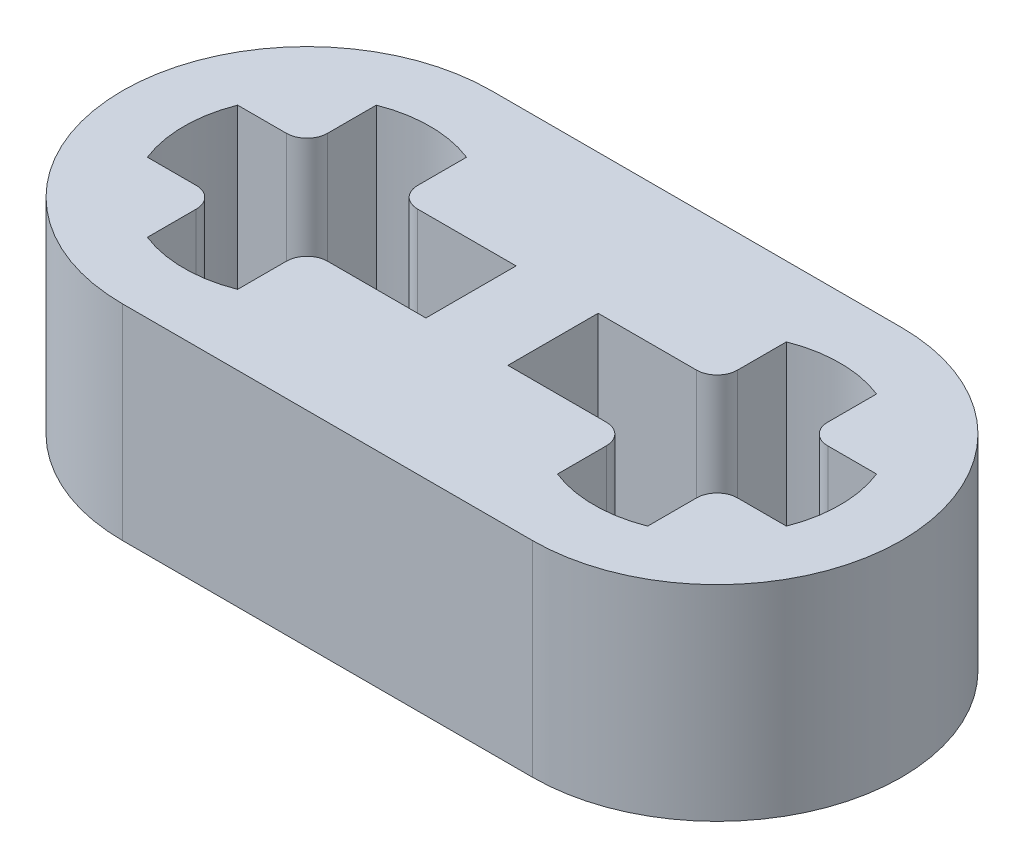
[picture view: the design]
ISO-10303-21;
HEADER;
FILE_DESCRIPTION(('STEP AP214'),'2;1');
FILE_NAME('part.step','',(''),(''),'','','');
FILE_SCHEMA(('AUTOMOTIVE_DESIGN { 1 0 10303 214 1 1 1 1 }'));
ENDSEC;
DATA;
#1=APPLICATION_CONTEXT('core data for automotive mechanical design processes');
#2=APPLICATION_PROTOCOL_DEFINITION('international standard','automotive_design',2000,#1);
#3=PRODUCT_CONTEXT('',#1,'mechanical');
#4=PRODUCT('Part','Part','',(#3));
#5=PRODUCT_RELATED_PRODUCT_CATEGORY('part','',(#4));
#6=PRODUCT_DEFINITION_FORMATION('','',#4);
#7=PRODUCT_DEFINITION_CONTEXT('part definition',#1,'design');
#8=PRODUCT_DEFINITION('design','',#6,#7);
#9=PRODUCT_DEFINITION_SHAPE('','',#8);
#10=(LENGTH_UNIT() NAMED_UNIT(*) SI_UNIT(.MILLI.,.METRE.));
#11=(NAMED_UNIT(*) PLANE_ANGLE_UNIT() SI_UNIT($,.RADIAN.));
#12=(NAMED_UNIT(*) SI_UNIT($,.STERADIAN.) SOLID_ANGLE_UNIT());
#13=UNCERTAINTY_MEASURE_WITH_UNIT(LENGTH_MEASURE(1.E-05),#10,'distance_accuracy_value','');
#14=(GEOMETRIC_REPRESENTATION_CONTEXT(3) GLOBAL_UNCERTAINTY_ASSIGNED_CONTEXT((#13)) GLOBAL_UNIT_ASSIGNED_CONTEXT((#10,
#11,#12)) REPRESENTATION_CONTEXT('',''));
#15=CARTESIAN_POINT('',(0.,0.,0.));
#16=DIRECTION('',(0.,0.,1.));
#17=DIRECTION('',(1.,0.,0.));
#18=AXIS2_PLACEMENT_3D('',#15,#16,#17);
#19=CARTESIAN_POINT('',(-4.,-2.,0.));
#20=DIRECTION('',(0.,1.,0.));
#21=DIRECTION('',(0.,0.,1.));
#22=AXIS2_PLACEMENT_3D('',#19,#20,#21);
#23=CYLINDRICAL_SURFACE('',#22,3.6);
#24=DIRECTION('',(0.,1.,0.));
#25=VECTOR('',#24,1.);
#26=CARTESIAN_POINT('',(-4.,-2.,3.6));
#27=LINE('',#26,#25);
#28=CARTESIAN_POINT('',(-4.,-2.,3.6));
#29=VERTEX_POINT('',#28);
#30=CARTESIAN_POINT('',(-4.,2.,3.6));
#31=VERTEX_POINT('',#30);
#32=EDGE_CURVE('E37',#29,#31,#27,.T.);
#33=ORIENTED_EDGE('',*,*,#32,.T.);
#34=CARTESIAN_POINT('',(-4.,2.,0.));
#35=DIRECTION('',(0.,1.,0.));
#36=DIRECTION('',(0.,0.,1.));
#37=AXIS2_PLACEMENT_3D('',#34,#35,#36);
#38=CIRCLE('',#37,3.6);
#39=CARTESIAN_POINT('',(-4.,2.,-3.6));
#40=VERTEX_POINT('',#39);
#41=EDGE_CURVE('E382',#40,#31,#38,.T.);
#42=ORIENTED_EDGE('',*,*,#41,.F.);
#43=DIRECTION('',(0.,1.,0.));
#44=VECTOR('',#43,1.);
#45=CARTESIAN_POINT('',(-4.,-2.,-3.6));
#46=LINE('',#45,#44);
#47=CARTESIAN_POINT('',(-4.,-2.,-3.6));
#48=VERTEX_POINT('',#47);
#49=EDGE_CURVE('E11',#48,#40,#46,.T.);
#50=ORIENTED_EDGE('',*,*,#49,.F.);
#51=CARTESIAN_POINT('',(-4.,-2.,0.));
#52=DIRECTION('',(0.,1.,0.));
#53=DIRECTION('',(0.,0.,1.));
#54=AXIS2_PLACEMENT_3D('',#51,#52,#53);
#55=CIRCLE('',#54,3.6);
#56=EDGE_CURVE('E513',#48,#29,#55,.T.);
#57=ORIENTED_EDGE('',*,*,#56,.T.);
#58=EDGE_LOOP('',(#33,#42,#50,#57));
#59=FACE_BOUND('',#58,.T.);
#60=ADVANCED_FACE('F34',(#59),#23,.T.);
#61=CARTESIAN_POINT('',(-4.,-2.,-3.6));
#62=DIRECTION('',(0.,0.,-1.));
#63=DIRECTION('',(-1.,0.,0.));
#64=AXIS2_PLACEMENT_3D('',#61,#62,#63);
#65=PLANE('',#64);
#66=ORIENTED_EDGE('',*,*,#49,.T.);
#67=DIRECTION('',(-1.,0.,0.));
#68=VECTOR('',#67,1.);
#69=CARTESIAN_POINT('',(-4.,2.,-3.6));
#70=LINE('',#69,#68);
#71=CARTESIAN_POINT('',(4.,2.,-3.6));
#72=VERTEX_POINT('',#71);
#73=EDGE_CURVE('E391',#72,#40,#70,.T.);
#74=ORIENTED_EDGE('',*,*,#73,.F.);
#75=DIRECTION('',(0.,1.,0.));
#76=VECTOR('',#75,1.);
#77=CARTESIAN_POINT('',(4.,-2.,-3.6));
#78=LINE('',#77,#76);
#79=CARTESIAN_POINT('',(4.,-2.,-3.6));
#80=VERTEX_POINT('',#79);
#81=EDGE_CURVE('E42',#80,#72,#78,.T.);
#82=ORIENTED_EDGE('',*,*,#81,.F.);
#83=DIRECTION('',(-1.,0.,0.));
#84=VECTOR('',#83,1.);
#85=CARTESIAN_POINT('',(-4.,-2.,-3.6));
#86=LINE('',#85,#84);
#87=EDGE_CURVE('E551',#80,#48,#86,.T.);
#88=ORIENTED_EDGE('',*,*,#87,.T.);
#89=EDGE_LOOP('',(#66,#74,#82,#88));
#90=FACE_BOUND('',#89,.T.);
#91=ADVANCED_FACE('F567',(#90),#65,.T.);
#92=CARTESIAN_POINT('',(4.,-2.,0.));
#93=DIRECTION('',(0.,1.,0.));
#94=DIRECTION('',(0.,0.,1.));
#95=AXIS2_PLACEMENT_3D('',#92,#93,#94);
#96=CYLINDRICAL_SURFACE('',#95,3.6);
#97=ORIENTED_EDGE('',*,*,#81,.T.);
#98=CARTESIAN_POINT('',(4.,2.,0.));
#99=DIRECTION('',(0.,1.,0.));
#100=DIRECTION('',(0.,0.,1.));
#101=AXIS2_PLACEMENT_3D('',#98,#99,#100);
#102=CIRCLE('',#101,3.6);
#103=CARTESIAN_POINT('',(4.,2.,3.6));
#104=VERTEX_POINT('',#103);
#105=EDGE_CURVE('E388',#104,#72,#102,.T.);
#106=ORIENTED_EDGE('',*,*,#105,.F.);
#107=DIRECTION('',(0.,1.,0.));
#108=VECTOR('',#107,1.);
#109=CARTESIAN_POINT('',(4.,-2.,3.6));
#110=LINE('',#109,#108);
#111=CARTESIAN_POINT('',(4.,-2.,3.6));
#112=VERTEX_POINT('',#111);
#113=EDGE_CURVE('E554',#112,#104,#110,.T.);
#114=ORIENTED_EDGE('',*,*,#113,.F.);
#115=CARTESIAN_POINT('',(4.,-2.,0.));
#116=DIRECTION('',(0.,1.,0.));
#117=DIRECTION('',(0.,0.,1.));
#118=AXIS2_PLACEMENT_3D('',#115,#116,#117);
#119=CIRCLE('',#118,3.6);
#120=EDGE_CURVE('E548',#112,#80,#119,.T.);
#121=ORIENTED_EDGE('',*,*,#120,.T.);
#122=EDGE_LOOP('',(#97,#106,#114,#121));
#123=FACE_BOUND('',#122,.T.);
#124=ADVANCED_FACE('F573',(#123),#96,.T.);
#125=CARTESIAN_POINT('',(-4.,-2.,3.6));
#126=DIRECTION('',(0.,0.,1.));
#127=DIRECTION('',(1.,0.,0.));
#128=AXIS2_PLACEMENT_3D('',#125,#126,#127);
#129=PLANE('',#128);
#130=ORIENTED_EDGE('',*,*,#113,.T.);
#131=DIRECTION('',(1.,0.,0.));
#132=VECTOR('',#131,1.);
#133=CARTESIAN_POINT('',(-4.,2.,3.6));
#134=LINE('',#133,#132);
#135=EDGE_CURVE('E385',#31,#104,#134,.T.);
#136=ORIENTED_EDGE('',*,*,#135,.F.);
#137=ORIENTED_EDGE('',*,*,#32,.F.);
#138=DIRECTION('',(1.,0.,0.));
#139=VECTOR('',#138,1.);
#140=CARTESIAN_POINT('',(-4.,-2.,3.6));
#141=LINE('',#140,#139);
#142=EDGE_CURVE('E545',#29,#112,#141,.T.);
#143=ORIENTED_EDGE('',*,*,#142,.T.);
#144=EDGE_LOOP('',(#130,#136,#137,#143));
#145=FACE_BOUND('',#144,.T.);
#146=ADVANCED_FACE('F561',(#145),#129,.T.);
#147=CARTESIAN_POINT('',(-4.,-2.,0.));
#148=DIRECTION('',(0.,1.,0.));
#149=DIRECTION('',(0.,0.,1.));
#150=AXIS2_PLACEMENT_3D('',#147,#148,#149);
#151=PLANE('',#150);
#152=DIRECTION('',(0.,0.,-1.));
#153=VECTOR('',#152,1.);
#154=CARTESIAN_POINT('',(4.88,-2.,-1.28));
#155=LINE('',#154,#153);
#156=CARTESIAN_POINT('',(4.88,-2.,-1.28));
#157=VERTEX_POINT('',#156);
#158=CARTESIAN_POINT('',(4.88,-2.,-2.23284571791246));
#159=VERTEX_POINT('',#158);
#160=EDGE_CURVE('E279',#157,#159,#155,.T.);
#161=ORIENTED_EDGE('',*,*,#160,.T.);
#162=CARTESIAN_POINT('',(4.,-2.,0.));
#163=DIRECTION('',(0.,1.,0.));
#164=DIRECTION('',(0.,0.,1.));
#165=AXIS2_PLACEMENT_3D('',#162,#163,#164);
#166=CIRCLE('',#165,2.4);
#167=CARTESIAN_POINT('',(3.12,-2.,-2.23284571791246));
#168=VERTEX_POINT('',#167);
#169=EDGE_CURVE('E394',#159,#168,#166,.T.);
#170=ORIENTED_EDGE('',*,*,#169,.T.);
#171=DIRECTION('',(0.,0.,1.));
#172=VECTOR('',#171,1.);
#173=CARTESIAN_POINT('',(3.12,-2.,-2.23284571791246));
#174=LINE('',#173,#172);
#175=CARTESIAN_POINT('',(3.12,-2.,-1.28));
#176=VERTEX_POINT('',#175);
#177=EDGE_CURVE('E274',#168,#176,#174,.T.);
#178=ORIENTED_EDGE('',*,*,#177,.T.);
#179=CARTESIAN_POINT('',(2.72,-2.,-1.28));
#180=DIRECTION('',(0.,-1.,0.));
#181=DIRECTION('',(0.,0.,-1.));
#182=AXIS2_PLACEMENT_3D('',#179,#180,#181);
#183=CIRCLE('',#182,0.4);
#184=CARTESIAN_POINT('',(2.72,-2.,-0.879999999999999));
#185=VERTEX_POINT('',#184);
#186=EDGE_CURVE('E50',#176,#185,#183,.T.);
#187=ORIENTED_EDGE('',*,*,#186,.T.);
#188=DIRECTION('',(-1.,0.,0.));
#189=VECTOR('',#188,1.);
#190=CARTESIAN_POINT('',(2.72,-2.,-0.879999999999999));
#191=LINE('',#190,#189);
#192=CARTESIAN_POINT('',(0.8,-2.,-0.879999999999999));
#193=VERTEX_POINT('',#192);
#194=EDGE_CURVE('E398',#185,#193,#191,.T.);
#195=ORIENTED_EDGE('',*,*,#194,.T.);
#196=DIRECTION('',(0.,0.,1.));
#197=VECTOR('',#196,1.);
#198=CARTESIAN_POINT('',(0.8,-2.,0.88));
#199=LINE('',#198,#197);
#200=CARTESIAN_POINT('',(0.8,-2.,0.88));
#201=VERTEX_POINT('',#200);
#202=EDGE_CURVE('E401',#193,#201,#199,.T.);
#203=ORIENTED_EDGE('',*,*,#202,.T.);
#204=DIRECTION('',(1.,0.,0.));
#205=VECTOR('',#204,1.);
#206=CARTESIAN_POINT('',(1.76715428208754,-2.,0.88));
#207=LINE('',#206,#205);
#208=CARTESIAN_POINT('',(2.72,-2.,0.88));
#209=VERTEX_POINT('',#208);
#210=EDGE_CURVE('E404',#201,#209,#207,.T.);
#211=ORIENTED_EDGE('',*,*,#210,.T.);
#212=CARTESIAN_POINT('',(2.72,-2.,1.28));
#213=DIRECTION('',(0.,-1.,0.));
#214=DIRECTION('',(0.,0.,1.));
#215=AXIS2_PLACEMENT_3D('',#212,#213,#214);
#216=CIRCLE('',#215,0.4);
#217=CARTESIAN_POINT('',(3.12,-2.,1.28));
#218=VERTEX_POINT('',#217);
#219=EDGE_CURVE('E407',#209,#218,#216,.T.);
#220=ORIENTED_EDGE('',*,*,#219,.T.);
#221=DIRECTION('',(0.,0.,1.));
#222=VECTOR('',#221,1.);
#223=CARTESIAN_POINT('',(3.12,-2.,1.28));
#224=LINE('',#223,#222);
#225=CARTESIAN_POINT('',(3.12,-2.,2.23284571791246));
#226=VERTEX_POINT('',#225);
#227=EDGE_CURVE('E410',#218,#226,#224,.T.);
#228=ORIENTED_EDGE('',*,*,#227,.T.);
#229=CARTESIAN_POINT('',(4.,-2.,0.));
#230=DIRECTION('',(0.,1.,0.));
#231=DIRECTION('',(0.,0.,1.));
#232=AXIS2_PLACEMENT_3D('',#229,#230,#231);
#233=CIRCLE('',#232,2.4);
#234=CARTESIAN_POINT('',(4.88,-2.,2.23284571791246));
#235=VERTEX_POINT('',#234);
#236=EDGE_CURVE('E413',#226,#235,#233,.T.);
#237=ORIENTED_EDGE('',*,*,#236,.T.);
#238=DIRECTION('',(0.,0.,-1.));
#239=VECTOR('',#238,1.);
#240=CARTESIAN_POINT('',(4.88,-2.,2.23284571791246));
#241=LINE('',#240,#239);
#242=CARTESIAN_POINT('',(4.88,-2.,1.28));
#243=VERTEX_POINT('',#242);
#244=EDGE_CURVE('E416',#235,#243,#241,.T.);
#245=ORIENTED_EDGE('',*,*,#244,.T.);
#246=CARTESIAN_POINT('',(5.28,-2.,1.28));
#247=DIRECTION('',(0.,-1.,0.));
#248=DIRECTION('',(0.,0.,-1.));
#249=AXIS2_PLACEMENT_3D('',#246,#247,#248);
#250=CIRCLE('',#249,0.4);
#251=CARTESIAN_POINT('',(5.28,-2.,0.88));
#252=VERTEX_POINT('',#251);
#253=EDGE_CURVE('E419',#243,#252,#250,.T.);
#254=ORIENTED_EDGE('',*,*,#253,.T.);
#255=DIRECTION('',(1.,0.,0.));
#256=VECTOR('',#255,1.);
#257=CARTESIAN_POINT('',(5.28,-2.,0.88));
#258=LINE('',#257,#256);
#259=CARTESIAN_POINT('',(6.23284571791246,-2.,0.88));
#260=VERTEX_POINT('',#259);
#261=EDGE_CURVE('E422',#252,#260,#258,.T.);
#262=ORIENTED_EDGE('',*,*,#261,.T.);
#263=CARTESIAN_POINT('',(4.,-2.,0.));
#264=DIRECTION('',(0.,1.,0.));
#265=DIRECTION('',(0.,0.,1.));
#266=AXIS2_PLACEMENT_3D('',#263,#264,#265);
#267=CIRCLE('',#266,2.4);
#268=CARTESIAN_POINT('',(6.23284571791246,-2.,-0.879999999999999));
#269=VERTEX_POINT('',#268);
#270=EDGE_CURVE('E425',#260,#269,#267,.T.);
#271=ORIENTED_EDGE('',*,*,#270,.T.);
#272=DIRECTION('',(-1.,0.,0.));
#273=VECTOR('',#272,1.);
#274=CARTESIAN_POINT('',(6.23284571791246,-2.,-0.879999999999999));
#275=LINE('',#274,#273);
#276=CARTESIAN_POINT('',(5.28,-2.,-0.879999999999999));
#277=VERTEX_POINT('',#276);
#278=EDGE_CURVE('E428',#269,#277,#275,.T.);
#279=ORIENTED_EDGE('',*,*,#278,.T.);
#280=CARTESIAN_POINT('',(5.28,-2.,-1.28));
#281=DIRECTION('',(0.,-1.,0.));
#282=DIRECTION('',(0.,0.,-1.));
#283=AXIS2_PLACEMENT_3D('',#280,#281,#282);
#284=CIRCLE('',#283,0.4);
#285=EDGE_CURVE('E431',#277,#157,#284,.T.);
#286=ORIENTED_EDGE('',*,*,#285,.T.);
#287=EDGE_LOOP('',(#161,#170,#178,#187,#195,#203,#211,#220,#228,#237,#245,#254,#262,#271,#279,#286));
#288=FACE_BOUND('',#287,.T.);
#289=DIRECTION('',(-1.,0.,0.));
#290=VECTOR('',#289,1.);
#291=CARTESIAN_POINT('',(-5.28,-2.,-0.88));
#292=LINE('',#291,#290);
#293=CARTESIAN_POINT('',(-5.28,-2.,-0.88));
#294=VERTEX_POINT('',#293);
#295=CARTESIAN_POINT('',(-6.23284571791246,-2.,-0.88));
#296=VERTEX_POINT('',#295);
#297=EDGE_CURVE('E507',#294,#296,#292,.T.);
#298=ORIENTED_EDGE('',*,*,#297,.T.);
#299=CARTESIAN_POINT('',(-4.,-2.,0.));
#300=DIRECTION('',(0.,1.,0.));
#301=DIRECTION('',(0.,0.,1.));
#302=AXIS2_PLACEMENT_3D('',#299,#300,#301);
#303=CIRCLE('',#302,2.4);
#304=CARTESIAN_POINT('',(-6.23284571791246,-2.,0.88));
#305=VERTEX_POINT('',#304);
#306=EDGE_CURVE('E437',#296,#305,#303,.T.);
#307=ORIENTED_EDGE('',*,*,#306,.T.);
#308=DIRECTION('',(1.,0.,0.));
#309=VECTOR('',#308,1.);
#310=CARTESIAN_POINT('',(-6.23284571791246,-2.,0.88));
#311=LINE('',#310,#309);
#312=CARTESIAN_POINT('',(-5.28,-2.,0.88));
#313=VERTEX_POINT('',#312);
#314=EDGE_CURVE('E467',#305,#313,#311,.T.);
#315=ORIENTED_EDGE('',*,*,#314,.T.);
#316=CARTESIAN_POINT('',(-5.28,-2.,1.28));
#317=DIRECTION('',(0.,-1.,0.));
#318=DIRECTION('',(0.,0.,1.));
#319=AXIS2_PLACEMENT_3D('',#316,#317,#318);
#320=CIRCLE('',#319,0.4);
#321=CARTESIAN_POINT('',(-4.88,-2.,1.28));
#322=VERTEX_POINT('',#321);
#323=EDGE_CURVE('E58',#313,#322,#320,.T.);
#324=ORIENTED_EDGE('',*,*,#323,.T.);
#325=DIRECTION('',(0.,0.,1.));
#326=VECTOR('',#325,1.);
#327=CARTESIAN_POINT('',(-4.88,-2.,1.28));
#328=LINE('',#327,#326);
#329=CARTESIAN_POINT('',(-4.88,-2.,2.23284571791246));
#330=VERTEX_POINT('',#329);
#331=EDGE_CURVE('E471',#322,#330,#328,.T.);
#332=ORIENTED_EDGE('',*,*,#331,.T.);
#333=CARTESIAN_POINT('',(-4.,-2.,0.));
#334=DIRECTION('',(0.,1.,0.));
#335=DIRECTION('',(0.,0.,1.));
#336=AXIS2_PLACEMENT_3D('',#333,#334,#335);
#337=CIRCLE('',#336,2.4);
#338=CARTESIAN_POINT('',(-3.12,-2.,2.23284571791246));
#339=VERTEX_POINT('',#338);
#340=EDGE_CURVE('E474',#330,#339,#337,.T.);
#341=ORIENTED_EDGE('',*,*,#340,.T.);
#342=DIRECTION('',(0.,0.,-1.));
#343=VECTOR('',#342,1.);
#344=CARTESIAN_POINT('',(-3.12,-2.,2.23284571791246));
#345=LINE('',#344,#343);
#346=CARTESIAN_POINT('',(-3.12,-2.,1.28));
#347=VERTEX_POINT('',#346);
#348=EDGE_CURVE('E477',#339,#347,#345,.T.);
#349=ORIENTED_EDGE('',*,*,#348,.T.);
#350=CARTESIAN_POINT('',(-2.72,-2.,1.28));
#351=DIRECTION('',(0.,-1.,0.));
#352=DIRECTION('',(0.,0.,-1.));
#353=AXIS2_PLACEMENT_3D('',#350,#351,#352);
#354=CIRCLE('',#353,0.4);
#355=CARTESIAN_POINT('',(-2.72,-2.,0.88));
#356=VERTEX_POINT('',#355);
#357=EDGE_CURVE('E480',#347,#356,#354,.T.);
#358=ORIENTED_EDGE('',*,*,#357,.T.);
#359=DIRECTION('',(1.,0.,0.));
#360=VECTOR('',#359,1.);
#361=CARTESIAN_POINT('',(-2.72,-2.,0.88));
#362=LINE('',#361,#360);
#363=CARTESIAN_POINT('',(-0.8,-2.,0.880000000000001));
#364=VERTEX_POINT('',#363);
#365=EDGE_CURVE('E483',#356,#364,#362,.T.);
#366=ORIENTED_EDGE('',*,*,#365,.T.);
#367=DIRECTION('',(0.,0.,-1.));
#368=VECTOR('',#367,1.);
#369=CARTESIAN_POINT('',(-0.8,-2.,-0.88));
#370=LINE('',#369,#368);
#371=CARTESIAN_POINT('',(-0.8,-2.,-0.88));
#372=VERTEX_POINT('',#371);
#373=EDGE_CURVE('E486',#364,#372,#370,.T.);
#374=ORIENTED_EDGE('',*,*,#373,.T.);
#375=DIRECTION('',(-1.,0.,0.));
#376=VECTOR('',#375,1.);
#377=CARTESIAN_POINT('',(-1.76715428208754,-2.,-0.88));
#378=LINE('',#377,#376);
#379=CARTESIAN_POINT('',(-2.72,-2.,-0.88));
#380=VERTEX_POINT('',#379);
#381=EDGE_CURVE('E489',#372,#380,#378,.T.);
#382=ORIENTED_EDGE('',*,*,#381,.T.);
#383=CARTESIAN_POINT('',(-2.72,-2.,-1.28));
#384=DIRECTION('',(0.,-1.,0.));
#385=DIRECTION('',(0.,0.,1.));
#386=AXIS2_PLACEMENT_3D('',#383,#384,#385);
#387=CIRCLE('',#386,0.4);
#388=CARTESIAN_POINT('',(-3.12,-2.,-1.28));
#389=VERTEX_POINT('',#388);
#390=EDGE_CURVE('E492',#380,#389,#387,.T.);
#391=ORIENTED_EDGE('',*,*,#390,.T.);
#392=DIRECTION('',(0.,0.,-1.));
#393=VECTOR('',#392,1.);
#394=CARTESIAN_POINT('',(-3.12,-2.,-1.28));
#395=LINE('',#394,#393);
#396=CARTESIAN_POINT('',(-3.12,-2.,-2.23284571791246));
#397=VERTEX_POINT('',#396);
#398=EDGE_CURVE('E495',#389,#397,#395,.T.);
#399=ORIENTED_EDGE('',*,*,#398,.T.);
#400=CARTESIAN_POINT('',(-4.,-2.,0.));
#401=DIRECTION('',(0.,1.,0.));
#402=DIRECTION('',(0.,0.,1.));
#403=AXIS2_PLACEMENT_3D('',#400,#401,#402);
#404=CIRCLE('',#403,2.4);
#405=CARTESIAN_POINT('',(-4.88,-2.,-2.23284571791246));
#406=VERTEX_POINT('',#405);
#407=EDGE_CURVE('E498',#397,#406,#404,.T.);
#408=ORIENTED_EDGE('',*,*,#407,.T.);
#409=DIRECTION('',(0.,0.,1.));
#410=VECTOR('',#409,1.);
#411=CARTESIAN_POINT('',(-4.88,-2.,-2.23284571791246));
#412=LINE('',#411,#410);
#413=CARTESIAN_POINT('',(-4.88,-2.,-1.28));
#414=VERTEX_POINT('',#413);
#415=EDGE_CURVE('E501',#406,#414,#412,.T.);
#416=ORIENTED_EDGE('',*,*,#415,.T.);
#417=CARTESIAN_POINT('',(-5.28,-2.,-1.28));
#418=DIRECTION('',(0.,-1.,0.));
#419=DIRECTION('',(0.,0.,1.));
#420=AXIS2_PLACEMENT_3D('',#417,#418,#419);
#421=CIRCLE('',#420,0.4);
#422=EDGE_CURVE('E504',#414,#294,#421,.T.);
#423=ORIENTED_EDGE('',*,*,#422,.T.);
#424=EDGE_LOOP('',(#298,#307,#315,#324,#332,#341,#349,#358,#366,#374,#382,#391,#399,#408,#416,#423));
#425=FACE_BOUND('',#424,.T.);
#426=ORIENTED_EDGE('',*,*,#56,.F.);
#427=ORIENTED_EDGE('',*,*,#87,.F.);
#428=ORIENTED_EDGE('',*,*,#120,.F.);
#429=ORIENTED_EDGE('',*,*,#142,.F.);
#430=EDGE_LOOP('',(#426,#427,#428,#429));
#431=FACE_BOUND('',#430,.T.);
#432=ADVANCED_FACE('F570',(#288,#425,#431),#151,.F.);
#433=CARTESIAN_POINT('',(-4.,-2.,0.));
#434=DIRECTION('',(0.,1.,0.));
#435=DIRECTION('',(0.,0.,1.));
#436=AXIS2_PLACEMENT_3D('',#433,#434,#435);
#437=CYLINDRICAL_SURFACE('',#436,2.4);
#438=DIRECTION('',(0.,1.,0.));
#439=VECTOR('',#438,1.);
#440=CARTESIAN_POINT('',(-6.23284571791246,-2.,-0.88));
#441=LINE('',#440,#439);
#442=CARTESIAN_POINT('',(-6.23284571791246,2.,-0.88));
#443=VERTEX_POINT('',#442);
#444=EDGE_CURVE('E511',#296,#443,#441,.T.);
#445=ORIENTED_EDGE('',*,*,#444,.T.);
#446=CARTESIAN_POINT('',(-4.,2.,0.));
#447=DIRECTION('',(0.,1.,0.));
#448=DIRECTION('',(0.,0.,1.));
#449=AXIS2_PLACEMENT_3D('',#446,#447,#448);
#450=CIRCLE('',#449,2.4);
#451=CARTESIAN_POINT('',(-6.23284571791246,2.,0.88));
#452=VERTEX_POINT('',#451);
#453=EDGE_CURVE('E334',#443,#452,#450,.T.);
#454=ORIENTED_EDGE('',*,*,#453,.T.);
#455=DIRECTION('',(0.,1.,0.));
#456=VECTOR('',#455,1.);
#457=CARTESIAN_POINT('',(-6.23284571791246,-2.,0.88));
#458=LINE('',#457,#456);
#459=EDGE_CURVE('E510',#305,#452,#458,.T.);
#460=ORIENTED_EDGE('',*,*,#459,.F.);
#461=ORIENTED_EDGE('',*,*,#306,.F.);
#462=EDGE_LOOP('',(#445,#454,#460,#461));
#463=FACE_BOUND('',#462,.T.);
#464=ADVANCED_FACE('F607',(#463),#437,.F.);
#465=CARTESIAN_POINT('',(-5.28,-2.,-0.88));
#466=DIRECTION('',(0.,0.,-1.));
#467=DIRECTION('',(-1.,0.,0.));
#468=AXIS2_PLACEMENT_3D('',#465,#466,#467);
#469=PLANE('',#468);
#470=DIRECTION('',(0.,1.,0.));
#471=VECTOR('',#470,1.);
#472=CARTESIAN_POINT('',(-5.28,-2.,-0.88));
#473=LINE('',#472,#471);
#474=CARTESIAN_POINT('',(-5.28,2.,-0.88));
#475=VERTEX_POINT('',#474);
#476=EDGE_CURVE('E514',#294,#475,#473,.T.);
#477=ORIENTED_EDGE('',*,*,#476,.T.);
#478=DIRECTION('',(-1.,0.,0.));
#479=VECTOR('',#478,1.);
#480=CARTESIAN_POINT('',(-5.28,2.,-0.88));
#481=LINE('',#480,#479);
#482=EDGE_CURVE('E379',#475,#443,#481,.T.);
#483=ORIENTED_EDGE('',*,*,#482,.T.);
#484=ORIENTED_EDGE('',*,*,#444,.F.);
#485=ORIENTED_EDGE('',*,*,#297,.F.);
#486=EDGE_LOOP('',(#477,#483,#484,#485));
#487=FACE_BOUND('',#486,.T.);
#488=ADVANCED_FACE('F617',(#487),#469,.F.);
#489=CARTESIAN_POINT('',(-5.28,-2.,-1.28));
#490=DIRECTION('',(0.,1.,0.));
#491=DIRECTION('',(0.,0.,1.));
#492=AXIS2_PLACEMENT_3D('',#489,#490,#491);
#493=CYLINDRICAL_SURFACE('',#492,0.4);
#494=DIRECTION('',(0.,1.,0.));
#495=VECTOR('',#494,1.);
#496=CARTESIAN_POINT('',(-4.88,-2.,-1.28));
#497=LINE('',#496,#495);
#498=CARTESIAN_POINT('',(-4.88,2.,-1.28));
#499=VERTEX_POINT('',#498);
#500=EDGE_CURVE('E516',#414,#499,#497,.T.);
#501=ORIENTED_EDGE('',*,*,#500,.T.);
#502=CARTESIAN_POINT('',(-5.28,2.,-1.28));
#503=DIRECTION('',(0.,-1.,0.));
#504=DIRECTION('',(0.,0.,1.));
#505=AXIS2_PLACEMENT_3D('',#502,#503,#504);
#506=CIRCLE('',#505,0.4);
#507=EDGE_CURVE('E376',#499,#475,#506,.T.);
#508=ORIENTED_EDGE('',*,*,#507,.T.);
#509=ORIENTED_EDGE('',*,*,#476,.F.);
#510=ORIENTED_EDGE('',*,*,#422,.F.);
#511=EDGE_LOOP('',(#501,#508,#509,#510));
#512=FACE_BOUND('',#511,.T.);
#513=ADVANCED_FACE('F627',(#512),#493,.T.);
#514=CARTESIAN_POINT('',(-4.88,-2.,-2.23284571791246));
#515=DIRECTION('',(-1.,0.,0.));
#516=DIRECTION('',(0.,0.,1.));
#517=AXIS2_PLACEMENT_3D('',#514,#515,#516);
#518=PLANE('',#517);
#519=DIRECTION('',(0.,1.,0.));
#520=VECTOR('',#519,1.);
#521=CARTESIAN_POINT('',(-4.88,-2.,-2.23284571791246));
#522=LINE('',#521,#520);
#523=CARTESIAN_POINT('',(-4.88,2.,-2.23284571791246));
#524=VERTEX_POINT('',#523);
#525=EDGE_CURVE('E518',#406,#524,#522,.T.);
#526=ORIENTED_EDGE('',*,*,#525,.T.);
#527=DIRECTION('',(0.,0.,1.));
#528=VECTOR('',#527,1.);
#529=CARTESIAN_POINT('',(-4.88,2.,-2.23284571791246));
#530=LINE('',#529,#528);
#531=EDGE_CURVE('E373',#524,#499,#530,.T.);
#532=ORIENTED_EDGE('',*,*,#531,.T.);
#533=ORIENTED_EDGE('',*,*,#500,.F.);
#534=ORIENTED_EDGE('',*,*,#415,.F.);
#535=EDGE_LOOP('',(#526,#532,#533,#534));
#536=FACE_BOUND('',#535,.T.);
#537=ADVANCED_FACE('F637',(#536),#518,.F.);
#538=CARTESIAN_POINT('',(-4.,-2.,0.));
#539=DIRECTION('',(0.,1.,0.));
#540=DIRECTION('',(0.,0.,1.));
#541=AXIS2_PLACEMENT_3D('',#538,#539,#540);
#542=CYLINDRICAL_SURFACE('',#541,2.4);
#543=DIRECTION('',(0.,1.,0.));
#544=VECTOR('',#543,1.);
#545=CARTESIAN_POINT('',(-3.12,-2.,-2.23284571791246));
#546=LINE('',#545,#544);
#547=CARTESIAN_POINT('',(-3.12,2.,-2.23284571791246));
#548=VERTEX_POINT('',#547);
#549=EDGE_CURVE('E520',#397,#548,#546,.T.);
#550=ORIENTED_EDGE('',*,*,#549,.T.);
#551=CARTESIAN_POINT('',(-4.,2.,0.));
#552=DIRECTION('',(0.,1.,0.));
#553=DIRECTION('',(0.,0.,1.));
#554=AXIS2_PLACEMENT_3D('',#551,#552,#553);
#555=CIRCLE('',#554,2.4);
#556=EDGE_CURVE('E370',#548,#524,#555,.T.);
#557=ORIENTED_EDGE('',*,*,#556,.T.);
#558=ORIENTED_EDGE('',*,*,#525,.F.);
#559=ORIENTED_EDGE('',*,*,#407,.F.);
#560=EDGE_LOOP('',(#550,#557,#558,#559));
#561=FACE_BOUND('',#560,.T.);
#562=ADVANCED_FACE('F647',(#561),#542,.F.);
#563=CARTESIAN_POINT('',(-3.12,-2.,-1.28));
#564=DIRECTION('',(1.,0.,0.));
#565=DIRECTION('',(0.,0.,-1.));
#566=AXIS2_PLACEMENT_3D('',#563,#564,#565);
#567=PLANE('',#566);
#568=DIRECTION('',(0.,1.,0.));
#569=VECTOR('',#568,1.);
#570=CARTESIAN_POINT('',(-3.12,-2.,-1.28));
#571=LINE('',#570,#569);
#572=CARTESIAN_POINT('',(-3.12,2.,-1.28));
#573=VERTEX_POINT('',#572);
#574=EDGE_CURVE('E522',#389,#573,#571,.T.);
#575=ORIENTED_EDGE('',*,*,#574,.T.);
#576=DIRECTION('',(0.,0.,-1.));
#577=VECTOR('',#576,1.);
#578=CARTESIAN_POINT('',(-3.12,2.,-1.28));
#579=LINE('',#578,#577);
#580=EDGE_CURVE('E367',#573,#548,#579,.T.);
#581=ORIENTED_EDGE('',*,*,#580,.T.);
#582=ORIENTED_EDGE('',*,*,#549,.F.);
#583=ORIENTED_EDGE('',*,*,#398,.F.);
#584=EDGE_LOOP('',(#575,#581,#582,#583));
#585=FACE_BOUND('',#584,.T.);
#586=ADVANCED_FACE('F657',(#585),#567,.F.);
#587=CARTESIAN_POINT('',(-2.72,-2.,-1.28));
#588=DIRECTION('',(0.,1.,0.));
#589=DIRECTION('',(0.,0.,1.));
#590=AXIS2_PLACEMENT_3D('',#587,#588,#589);
#591=CYLINDRICAL_SURFACE('',#590,0.4);
#592=DIRECTION('',(0.,1.,0.));
#593=VECTOR('',#592,1.);
#594=CARTESIAN_POINT('',(-2.72,-2.,-0.88));
#595=LINE('',#594,#593);
#596=CARTESIAN_POINT('',(-2.72,2.,-0.88));
#597=VERTEX_POINT('',#596);
#598=EDGE_CURVE('E524',#380,#597,#595,.T.);
#599=ORIENTED_EDGE('',*,*,#598,.T.);
#600=CARTESIAN_POINT('',(-2.72,2.,-1.28));
#601=DIRECTION('',(0.,-1.,0.));
#602=DIRECTION('',(0.,0.,1.));
#603=AXIS2_PLACEMENT_3D('',#600,#601,#602);
#604=CIRCLE('',#603,0.4);
#605=EDGE_CURVE('E364',#597,#573,#604,.T.);
#606=ORIENTED_EDGE('',*,*,#605,.T.);
#607=ORIENTED_EDGE('',*,*,#574,.F.);
#608=ORIENTED_EDGE('',*,*,#390,.F.);
#609=EDGE_LOOP('',(#599,#606,#607,#608));
#610=FACE_BOUND('',#609,.T.);
#611=ADVANCED_FACE('F667',(#610),#591,.T.);
#612=CARTESIAN_POINT('',(-1.76715428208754,-2.,-0.88));
#613=DIRECTION('',(0.,0.,-1.));
#614=DIRECTION('',(-1.,0.,0.));
#615=AXIS2_PLACEMENT_3D('',#612,#613,#614);
#616=PLANE('',#615);
#617=DIRECTION('',(0.,1.,0.));
#618=VECTOR('',#617,1.);
#619=CARTESIAN_POINT('',(-0.8,-2.,-0.88));
#620=LINE('',#619,#618);
#621=CARTESIAN_POINT('',(-0.8,2.,-0.88));
#622=VERTEX_POINT('',#621);
#623=EDGE_CURVE('E526',#372,#622,#620,.T.);
#624=ORIENTED_EDGE('',*,*,#623,.T.);
#625=DIRECTION('',(-1.,0.,0.));
#626=VECTOR('',#625,1.);
#627=CARTESIAN_POINT('',(-1.76715428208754,2.,-0.88));
#628=LINE('',#627,#626);
#629=EDGE_CURVE('E361',#622,#597,#628,.T.);
#630=ORIENTED_EDGE('',*,*,#629,.T.);
#631=ORIENTED_EDGE('',*,*,#598,.F.);
#632=ORIENTED_EDGE('',*,*,#381,.F.);
#633=EDGE_LOOP('',(#624,#630,#631,#632));
#634=FACE_BOUND('',#633,.T.);
#635=ADVANCED_FACE('F677',(#634),#616,.F.);
#636=CARTESIAN_POINT('',(-0.8,-2.,-0.88));
#637=DIRECTION('',(1.,0.,0.));
#638=DIRECTION('',(0.,0.,-1.));
#639=AXIS2_PLACEMENT_3D('',#636,#637,#638);
#640=PLANE('',#639);
#641=DIRECTION('',(0.,1.,0.));
#642=VECTOR('',#641,1.);
#643=CARTESIAN_POINT('',(-0.8,-2.,0.880000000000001));
#644=LINE('',#643,#642);
#645=CARTESIAN_POINT('',(-0.8,2.,0.880000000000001));
#646=VERTEX_POINT('',#645);
#647=EDGE_CURVE('E528',#364,#646,#644,.T.);
#648=ORIENTED_EDGE('',*,*,#647,.T.);
#649=DIRECTION('',(0.,0.,-1.));
#650=VECTOR('',#649,1.);
#651=CARTESIAN_POINT('',(-0.8,2.,-0.88));
#652=LINE('',#651,#650);
#653=EDGE_CURVE('E358',#646,#622,#652,.T.);
#654=ORIENTED_EDGE('',*,*,#653,.T.);
#655=ORIENTED_EDGE('',*,*,#623,.F.);
#656=ORIENTED_EDGE('',*,*,#373,.F.);
#657=EDGE_LOOP('',(#648,#654,#655,#656));
#658=FACE_BOUND('',#657,.T.);
#659=ADVANCED_FACE('F688',(#658),#640,.F.);
#660=CARTESIAN_POINT('',(-0.8,-2.,0.880000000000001));
#661=DIRECTION('',(0.,0.,1.));
#662=DIRECTION('',(1.,0.,0.));
#663=AXIS2_PLACEMENT_3D('',#660,#661,#662);
#664=PLANE('',#663);
#665=DIRECTION('',(0.,1.,0.));
#666=VECTOR('',#665,1.);
#667=CARTESIAN_POINT('',(-2.72,-2.,0.88));
#668=LINE('',#667,#666);
#669=CARTESIAN_POINT('',(-2.72,2.,0.88));
#670=VERTEX_POINT('',#669);
#671=EDGE_CURVE('E530',#356,#670,#668,.T.);
#672=ORIENTED_EDGE('',*,*,#671,.T.);
#673=DIRECTION('',(1.,0.,0.));
#674=VECTOR('',#673,1.);
#675=CARTESIAN_POINT('',(-2.72,2.,0.88));
#676=LINE('',#675,#674);
#677=EDGE_CURVE('E355',#670,#646,#676,.T.);
#678=ORIENTED_EDGE('',*,*,#677,.T.);
#679=ORIENTED_EDGE('',*,*,#647,.F.);
#680=ORIENTED_EDGE('',*,*,#365,.F.);
#681=EDGE_LOOP('',(#672,#678,#679,#680));
#682=FACE_BOUND('',#681,.T.);
#683=ADVANCED_FACE('F698',(#682),#664,.F.);
#684=CARTESIAN_POINT('',(-2.72,-2.,1.28));
#685=DIRECTION('',(0.,1.,0.));
#686=DIRECTION('',(0.,0.,1.));
#687=AXIS2_PLACEMENT_3D('',#684,#685,#686);
#688=CYLINDRICAL_SURFACE('',#687,0.4);
#689=DIRECTION('',(0.,1.,0.));
#690=VECTOR('',#689,1.);
#691=CARTESIAN_POINT('',(-3.12,-2.,1.28));
#692=LINE('',#691,#690);
#693=CARTESIAN_POINT('',(-3.12,2.,1.28));
#694=VERTEX_POINT('',#693);
#695=EDGE_CURVE('E532',#347,#694,#692,.T.);
#696=ORIENTED_EDGE('',*,*,#695,.T.);
#697=CARTESIAN_POINT('',(-2.72,2.,1.28));
#698=DIRECTION('',(0.,-1.,0.));
#699=DIRECTION('',(0.,0.,-1.));
#700=AXIS2_PLACEMENT_3D('',#697,#698,#699);
#701=CIRCLE('',#700,0.4);
#702=EDGE_CURVE('E352',#694,#670,#701,.T.);
#703=ORIENTED_EDGE('',*,*,#702,.T.);
#704=ORIENTED_EDGE('',*,*,#671,.F.);
#705=ORIENTED_EDGE('',*,*,#357,.F.);
#706=EDGE_LOOP('',(#696,#703,#704,#705));
#707=FACE_BOUND('',#706,.T.);
#708=ADVANCED_FACE('F709',(#707),#688,.T.);
#709=CARTESIAN_POINT('',(-3.12,-2.,2.23284571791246));
#710=DIRECTION('',(1.,0.,0.));
#711=DIRECTION('',(0.,0.,-1.));
#712=AXIS2_PLACEMENT_3D('',#709,#710,#711);
#713=PLANE('',#712);
#714=DIRECTION('',(0.,1.,0.));
#715=VECTOR('',#714,1.);
#716=CARTESIAN_POINT('',(-3.12,-2.,2.23284571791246));
#717=LINE('',#716,#715);
#718=CARTESIAN_POINT('',(-3.12,2.,2.23284571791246));
#719=VERTEX_POINT('',#718);
#720=EDGE_CURVE('E534',#339,#719,#717,.T.);
#721=ORIENTED_EDGE('',*,*,#720,.T.);
#722=DIRECTION('',(0.,0.,-1.));
#723=VECTOR('',#722,1.);
#724=CARTESIAN_POINT('',(-3.12,2.,2.23284571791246));
#725=LINE('',#724,#723);
#726=EDGE_CURVE('E349',#719,#694,#725,.T.);
#727=ORIENTED_EDGE('',*,*,#726,.T.);
#728=ORIENTED_EDGE('',*,*,#695,.F.);
#729=ORIENTED_EDGE('',*,*,#348,.F.);
#730=EDGE_LOOP('',(#721,#727,#728,#729));
#731=FACE_BOUND('',#730,.T.);
#732=ADVANCED_FACE('F719',(#731),#713,.F.);
#733=CARTESIAN_POINT('',(-4.,-2.,0.));
#734=DIRECTION('',(0.,1.,0.));
#735=DIRECTION('',(0.,0.,1.));
#736=AXIS2_PLACEMENT_3D('',#733,#734,#735);
#737=CYLINDRICAL_SURFACE('',#736,2.4);
#738=DIRECTION('',(0.,1.,0.));
#739=VECTOR('',#738,1.);
#740=CARTESIAN_POINT('',(-4.88,-2.,2.23284571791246));
#741=LINE('',#740,#739);
#742=CARTESIAN_POINT('',(-4.88,2.,2.23284571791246));
#743=VERTEX_POINT('',#742);
#744=EDGE_CURVE('E536',#330,#743,#741,.T.);
#745=ORIENTED_EDGE('',*,*,#744,.T.);
#746=CARTESIAN_POINT('',(-4.,2.,0.));
#747=DIRECTION('',(0.,1.,0.));
#748=DIRECTION('',(0.,0.,1.));
#749=AXIS2_PLACEMENT_3D('',#746,#747,#748);
#750=CIRCLE('',#749,2.4);
#751=EDGE_CURVE('E346',#743,#719,#750,.T.);
#752=ORIENTED_EDGE('',*,*,#751,.T.);
#753=ORIENTED_EDGE('',*,*,#720,.F.);
#754=ORIENTED_EDGE('',*,*,#340,.F.);
#755=EDGE_LOOP('',(#745,#752,#753,#754));
#756=FACE_BOUND('',#755,.T.);
#757=ADVANCED_FACE('F729',(#756),#737,.F.);
#758=CARTESIAN_POINT('',(-4.88,-2.,1.28));
#759=DIRECTION('',(-1.,0.,0.));
#760=DIRECTION('',(0.,0.,1.));
#761=AXIS2_PLACEMENT_3D('',#758,#759,#760);
#762=PLANE('',#761);
#763=DIRECTION('',(0.,1.,0.));
#764=VECTOR('',#763,1.);
#765=CARTESIAN_POINT('',(-4.88,-2.,1.28));
#766=LINE('',#765,#764);
#767=CARTESIAN_POINT('',(-4.88,2.,1.28));
#768=VERTEX_POINT('',#767);
#769=EDGE_CURVE('E538',#322,#768,#766,.T.);
#770=ORIENTED_EDGE('',*,*,#769,.T.);
#771=DIRECTION('',(0.,0.,1.));
#772=VECTOR('',#771,1.);
#773=CARTESIAN_POINT('',(-4.88,2.,1.28));
#774=LINE('',#773,#772);
#775=EDGE_CURVE('E343',#768,#743,#774,.T.);
#776=ORIENTED_EDGE('',*,*,#775,.T.);
#777=ORIENTED_EDGE('',*,*,#744,.F.);
#778=ORIENTED_EDGE('',*,*,#331,.F.);
#779=EDGE_LOOP('',(#770,#776,#777,#778));
#780=FACE_BOUND('',#779,.T.);
#781=ADVANCED_FACE('F739',(#780),#762,.F.);
#782=CARTESIAN_POINT('',(-5.28,-2.,1.28));
#783=DIRECTION('',(0.,1.,0.));
#784=DIRECTION('',(0.,0.,1.));
#785=AXIS2_PLACEMENT_3D('',#782,#783,#784);
#786=CYLINDRICAL_SURFACE('',#785,0.4);
#787=DIRECTION('',(0.,1.,0.));
#788=VECTOR('',#787,1.);
#789=CARTESIAN_POINT('',(-5.28,-2.,0.88));
#790=LINE('',#789,#788);
#791=CARTESIAN_POINT('',(-5.28,2.,0.88));
#792=VERTEX_POINT('',#791);
#793=EDGE_CURVE('E540',#313,#792,#790,.T.);
#794=ORIENTED_EDGE('',*,*,#793,.T.);
#795=CARTESIAN_POINT('',(-5.28,2.,1.28));
#796=DIRECTION('',(0.,-1.,0.));
#797=DIRECTION('',(0.,0.,1.));
#798=AXIS2_PLACEMENT_3D('',#795,#796,#797);
#799=CIRCLE('',#798,0.4);
#800=EDGE_CURVE('E340',#792,#768,#799,.T.);
#801=ORIENTED_EDGE('',*,*,#800,.T.);
#802=ORIENTED_EDGE('',*,*,#769,.F.);
#803=ORIENTED_EDGE('',*,*,#323,.F.);
#804=EDGE_LOOP('',(#794,#801,#802,#803));
#805=FACE_BOUND('',#804,.T.);
#806=ADVANCED_FACE('F749',(#805),#786,.T.);
#807=CARTESIAN_POINT('',(-6.23284571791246,-2.,0.88));
#808=DIRECTION('',(0.,0.,1.));
#809=DIRECTION('',(1.,0.,0.));
#810=AXIS2_PLACEMENT_3D('',#807,#808,#809);
#811=PLANE('',#810);
#812=ORIENTED_EDGE('',*,*,#459,.T.);
#813=DIRECTION('',(1.,0.,0.));
#814=VECTOR('',#813,1.);
#815=CARTESIAN_POINT('',(-6.23284571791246,2.,0.88));
#816=LINE('',#815,#814);
#817=EDGE_CURVE('E337',#452,#792,#816,.T.);
#818=ORIENTED_EDGE('',*,*,#817,.T.);
#819=ORIENTED_EDGE('',*,*,#793,.F.);
#820=ORIENTED_EDGE('',*,*,#314,.F.);
#821=EDGE_LOOP('',(#812,#818,#819,#820));
#822=FACE_BOUND('',#821,.T.);
#823=ADVANCED_FACE('F759',(#822),#811,.F.);
#824=CARTESIAN_POINT('',(4.,-2.,0.));
#825=DIRECTION('',(0.,1.,0.));
#826=DIRECTION('',(0.,0.,1.));
#827=AXIS2_PLACEMENT_3D('',#824,#825,#826);
#828=CYLINDRICAL_SURFACE('',#827,2.4);
#829=DIRECTION('',(0.,1.,0.));
#830=VECTOR('',#829,1.);
#831=CARTESIAN_POINT('',(4.88,-2.,-2.23284571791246));
#832=LINE('',#831,#830);
#833=CARTESIAN_POINT('',(4.88,2.,-2.23284571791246));
#834=VERTEX_POINT('',#833);
#835=EDGE_CURVE('E284',#159,#834,#832,.T.);
#836=ORIENTED_EDGE('',*,*,#835,.T.);
#837=CARTESIAN_POINT('',(4.,2.,0.));
#838=DIRECTION('',(0.,1.,0.));
#839=DIRECTION('',(0.,0.,1.));
#840=AXIS2_PLACEMENT_3D('',#837,#838,#839);
#841=CIRCLE('',#840,2.4);
#842=CARTESIAN_POINT('',(3.12,2.,-2.23284571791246));
#843=VERTEX_POINT('',#842);
#844=EDGE_CURVE('E282',#834,#843,#841,.T.);
#845=ORIENTED_EDGE('',*,*,#844,.T.);
#846=DIRECTION('',(0.,1.,0.));
#847=VECTOR('',#846,1.);
#848=CARTESIAN_POINT('',(3.12,-2.,-2.23284571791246));
#849=LINE('',#848,#847);
#850=EDGE_CURVE('E267',#168,#843,#849,.T.);
#851=ORIENTED_EDGE('',*,*,#850,.F.);
#852=ORIENTED_EDGE('',*,*,#169,.F.);
#853=EDGE_LOOP('',(#836,#845,#851,#852));
#854=FACE_BOUND('',#853,.T.);
#855=ADVANCED_FACE('F283',(#854),#828,.F.);
#856=CARTESIAN_POINT('',(4.88,-2.,-1.28));
#857=DIRECTION('',(1.,0.,0.));
#858=DIRECTION('',(0.,0.,-1.));
#859=AXIS2_PLACEMENT_3D('',#856,#857,#858);
#860=PLANE('',#859);
#861=DIRECTION('',(0.,1.,0.));
#862=VECTOR('',#861,1.);
#863=CARTESIAN_POINT('',(4.88,-2.,-1.28));
#864=LINE('',#863,#862);
#865=CARTESIAN_POINT('',(4.88,2.,-1.28));
#866=VERTEX_POINT('',#865);
#867=EDGE_CURVE('E438',#157,#866,#864,.T.);
#868=ORIENTED_EDGE('',*,*,#867,.T.);
#869=DIRECTION('',(0.,0.,-1.));
#870=VECTOR('',#869,1.);
#871=CARTESIAN_POINT('',(4.88,2.,-1.28));
#872=LINE('',#871,#870);
#873=EDGE_CURVE('E332',#866,#834,#872,.T.);
#874=ORIENTED_EDGE('',*,*,#873,.T.);
#875=ORIENTED_EDGE('',*,*,#835,.F.);
#876=ORIENTED_EDGE('',*,*,#160,.F.);
#877=EDGE_LOOP('',(#868,#874,#875,#876));
#878=FACE_BOUND('',#877,.T.);
#879=ADVANCED_FACE('F777',(#878),#860,.F.);
#880=CARTESIAN_POINT('',(5.28,-2.,-1.28));
#881=DIRECTION('',(0.,1.,0.));
#882=DIRECTION('',(0.,0.,1.));
#883=AXIS2_PLACEMENT_3D('',#880,#881,#882);
#884=CYLINDRICAL_SURFACE('',#883,0.4);
#885=DIRECTION('',(0.,1.,0.));
#886=VECTOR('',#885,1.);
#887=CARTESIAN_POINT('',(5.28,-2.,-0.879999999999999));
#888=LINE('',#887,#886);
#889=CARTESIAN_POINT('',(5.28,2.,-0.879999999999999));
#890=VERTEX_POINT('',#889);
#891=EDGE_CURVE('E440',#277,#890,#888,.T.);
#892=ORIENTED_EDGE('',*,*,#891,.T.);
#893=CARTESIAN_POINT('',(5.28,2.,-1.28));
#894=DIRECTION('',(0.,-1.,0.));
#895=DIRECTION('',(0.,0.,-1.));
#896=AXIS2_PLACEMENT_3D('',#893,#894,#895);
#897=CIRCLE('',#896,0.4);
#898=EDGE_CURVE('E329',#890,#866,#897,.T.);
#899=ORIENTED_EDGE('',*,*,#898,.T.);
#900=ORIENTED_EDGE('',*,*,#867,.F.);
#901=ORIENTED_EDGE('',*,*,#285,.F.);
#902=EDGE_LOOP('',(#892,#899,#900,#901));
#903=FACE_BOUND('',#902,.T.);
#904=ADVANCED_FACE('F786',(#903),#884,.T.);
#905=CARTESIAN_POINT('',(6.23284571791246,-2.,-0.879999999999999));
#906=DIRECTION('',(0.,0.,-1.));
#907=DIRECTION('',(-1.,0.,0.));
#908=AXIS2_PLACEMENT_3D('',#905,#906,#907);
#909=PLANE('',#908);
#910=DIRECTION('',(0.,1.,0.));
#911=VECTOR('',#910,1.);
#912=CARTESIAN_POINT('',(6.23284571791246,-2.,-0.879999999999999));
#913=LINE('',#912,#911);
#914=CARTESIAN_POINT('',(6.23284571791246,2.,-0.879999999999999));
#915=VERTEX_POINT('',#914);
#916=EDGE_CURVE('E442',#269,#915,#913,.T.);
#917=ORIENTED_EDGE('',*,*,#916,.T.);
#918=DIRECTION('',(-1.,0.,0.));
#919=VECTOR('',#918,1.);
#920=CARTESIAN_POINT('',(6.23284571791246,2.,-0.879999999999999));
#921=LINE('',#920,#919);
#922=EDGE_CURVE('E326',#915,#890,#921,.T.);
#923=ORIENTED_EDGE('',*,*,#922,.T.);
#924=ORIENTED_EDGE('',*,*,#891,.F.);
#925=ORIENTED_EDGE('',*,*,#278,.F.);
#926=EDGE_LOOP('',(#917,#923,#924,#925));
#927=FACE_BOUND('',#926,.T.);
#928=ADVANCED_FACE('F796',(#927),#909,.F.);
#929=CARTESIAN_POINT('',(4.,-2.,0.));
#930=DIRECTION('',(0.,1.,0.));
#931=DIRECTION('',(0.,0.,1.));
#932=AXIS2_PLACEMENT_3D('',#929,#930,#931);
#933=CYLINDRICAL_SURFACE('',#932,2.4);
#934=DIRECTION('',(0.,1.,0.));
#935=VECTOR('',#934,1.);
#936=CARTESIAN_POINT('',(6.23284571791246,-2.,0.88));
#937=LINE('',#936,#935);
#938=CARTESIAN_POINT('',(6.23284571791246,2.,0.88));
#939=VERTEX_POINT('',#938);
#940=EDGE_CURVE('E444',#260,#939,#937,.T.);
#941=ORIENTED_EDGE('',*,*,#940,.T.);
#942=CARTESIAN_POINT('',(4.,2.,0.));
#943=DIRECTION('',(0.,1.,0.));
#944=DIRECTION('',(0.,0.,1.));
#945=AXIS2_PLACEMENT_3D('',#942,#943,#944);
#946=CIRCLE('',#945,2.4);
#947=EDGE_CURVE('E323',#939,#915,#946,.T.);
#948=ORIENTED_EDGE('',*,*,#947,.T.);
#949=ORIENTED_EDGE('',*,*,#916,.F.);
#950=ORIENTED_EDGE('',*,*,#270,.F.);
#951=EDGE_LOOP('',(#941,#948,#949,#950));
#952=FACE_BOUND('',#951,.T.);
#953=ADVANCED_FACE('F806',(#952),#933,.F.);
#954=CARTESIAN_POINT('',(5.28,-2.,0.88));
#955=DIRECTION('',(0.,0.,1.));
#956=DIRECTION('',(1.,0.,0.));
#957=AXIS2_PLACEMENT_3D('',#954,#955,#956);
#958=PLANE('',#957);
#959=DIRECTION('',(0.,1.,0.));
#960=VECTOR('',#959,1.);
#961=CARTESIAN_POINT('',(5.28,-2.,0.88));
#962=LINE('',#961,#960);
#963=CARTESIAN_POINT('',(5.28,2.,0.88));
#964=VERTEX_POINT('',#963);
#965=EDGE_CURVE('E446',#252,#964,#962,.T.);
#966=ORIENTED_EDGE('',*,*,#965,.T.);
#967=DIRECTION('',(1.,0.,0.));
#968=VECTOR('',#967,1.);
#969=CARTESIAN_POINT('',(5.28,2.,0.88));
#970=LINE('',#969,#968);
#971=EDGE_CURVE('E320',#964,#939,#970,.T.);
#972=ORIENTED_EDGE('',*,*,#971,.T.);
#973=ORIENTED_EDGE('',*,*,#940,.F.);
#974=ORIENTED_EDGE('',*,*,#261,.F.);
#975=EDGE_LOOP('',(#966,#972,#973,#974));
#976=FACE_BOUND('',#975,.T.);
#977=ADVANCED_FACE('F816',(#976),#958,.F.);
#978=CARTESIAN_POINT('',(5.28,-2.,1.28));
#979=DIRECTION('',(0.,1.,0.));
#980=DIRECTION('',(0.,0.,1.));
#981=AXIS2_PLACEMENT_3D('',#978,#979,#980);
#982=CYLINDRICAL_SURFACE('',#981,0.4);
#983=DIRECTION('',(0.,1.,0.));
#984=VECTOR('',#983,1.);
#985=CARTESIAN_POINT('',(4.88,-2.,1.28));
#986=LINE('',#985,#984);
#987=CARTESIAN_POINT('',(4.88,2.,1.28));
#988=VERTEX_POINT('',#987);
#989=EDGE_CURVE('E448',#243,#988,#986,.T.);
#990=ORIENTED_EDGE('',*,*,#989,.T.);
#991=CARTESIAN_POINT('',(5.28,2.,1.28));
#992=DIRECTION('',(0.,-1.,0.));
#993=DIRECTION('',(0.,0.,-1.));
#994=AXIS2_PLACEMENT_3D('',#991,#992,#993);
#995=CIRCLE('',#994,0.4);
#996=EDGE_CURVE('E317',#988,#964,#995,.T.);
#997=ORIENTED_EDGE('',*,*,#996,.T.);
#998=ORIENTED_EDGE('',*,*,#965,.F.);
#999=ORIENTED_EDGE('',*,*,#253,.F.);
#1000=EDGE_LOOP('',(#990,#997,#998,#999));
#1001=FACE_BOUND('',#1000,.T.);
#1002=ADVANCED_FACE('F826',(#1001),#982,.T.);
#1003=CARTESIAN_POINT('',(4.88,-2.,2.23284571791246));
#1004=DIRECTION('',(1.,0.,0.));
#1005=DIRECTION('',(0.,0.,-1.));
#1006=AXIS2_PLACEMENT_3D('',#1003,#1004,#1005);
#1007=PLANE('',#1006);
#1008=DIRECTION('',(0.,1.,0.));
#1009=VECTOR('',#1008,1.);
#1010=CARTESIAN_POINT('',(4.88,-2.,2.23284571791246));
#1011=LINE('',#1010,#1009);
#1012=CARTESIAN_POINT('',(4.88,2.,2.23284571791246));
#1013=VERTEX_POINT('',#1012);
#1014=EDGE_CURVE('E450',#235,#1013,#1011,.T.);
#1015=ORIENTED_EDGE('',*,*,#1014,.T.);
#1016=DIRECTION('',(0.,0.,-1.));
#1017=VECTOR('',#1016,1.);
#1018=CARTESIAN_POINT('',(4.88,2.,2.23284571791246));
#1019=LINE('',#1018,#1017);
#1020=EDGE_CURVE('E314',#1013,#988,#1019,.T.);
#1021=ORIENTED_EDGE('',*,*,#1020,.T.);
#1022=ORIENTED_EDGE('',*,*,#989,.F.);
#1023=ORIENTED_EDGE('',*,*,#244,.F.);
#1024=EDGE_LOOP('',(#1015,#1021,#1022,#1023));
#1025=FACE_BOUND('',#1024,.T.);
#1026=ADVANCED_FACE('F836',(#1025),#1007,.F.);
#1027=CARTESIAN_POINT('',(4.,-2.,0.));
#1028=DIRECTION('',(0.,1.,0.));
#1029=DIRECTION('',(0.,0.,1.));
#1030=AXIS2_PLACEMENT_3D('',#1027,#1028,#1029);
#1031=CYLINDRICAL_SURFACE('',#1030,2.4);
#1032=DIRECTION('',(0.,1.,0.));
#1033=VECTOR('',#1032,1.);
#1034=CARTESIAN_POINT('',(3.12,-2.,2.23284571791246));
#1035=LINE('',#1034,#1033);
#1036=CARTESIAN_POINT('',(3.12,2.,2.23284571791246));
#1037=VERTEX_POINT('',#1036);
#1038=EDGE_CURVE('E452',#226,#1037,#1035,.T.);
#1039=ORIENTED_EDGE('',*,*,#1038,.T.);
#1040=CARTESIAN_POINT('',(4.,2.,0.));
#1041=DIRECTION('',(0.,1.,0.));
#1042=DIRECTION('',(0.,0.,1.));
#1043=AXIS2_PLACEMENT_3D('',#1040,#1041,#1042);
#1044=CIRCLE('',#1043,2.4);
#1045=EDGE_CURVE('E311',#1037,#1013,#1044,.T.);
#1046=ORIENTED_EDGE('',*,*,#1045,.T.);
#1047=ORIENTED_EDGE('',*,*,#1014,.F.);
#1048=ORIENTED_EDGE('',*,*,#236,.F.);
#1049=EDGE_LOOP('',(#1039,#1046,#1047,#1048));
#1050=FACE_BOUND('',#1049,.T.);
#1051=ADVANCED_FACE('F846',(#1050),#1031,.F.);
#1052=CARTESIAN_POINT('',(3.12,-2.,1.28));
#1053=DIRECTION('',(-1.,0.,0.));
#1054=DIRECTION('',(0.,0.,1.));
#1055=AXIS2_PLACEMENT_3D('',#1052,#1053,#1054);
#1056=PLANE('',#1055);
#1057=DIRECTION('',(0.,1.,0.));
#1058=VECTOR('',#1057,1.);
#1059=CARTESIAN_POINT('',(3.12,-2.,1.28));
#1060=LINE('',#1059,#1058);
#1061=CARTESIAN_POINT('',(3.12,2.,1.28));
#1062=VERTEX_POINT('',#1061);
#1063=EDGE_CURVE('E454',#218,#1062,#1060,.T.);
#1064=ORIENTED_EDGE('',*,*,#1063,.T.);
#1065=DIRECTION('',(0.,0.,1.));
#1066=VECTOR('',#1065,1.);
#1067=CARTESIAN_POINT('',(3.12,2.,1.28));
#1068=LINE('',#1067,#1066);
#1069=EDGE_CURVE('E308',#1062,#1037,#1068,.T.);
#1070=ORIENTED_EDGE('',*,*,#1069,.T.);
#1071=ORIENTED_EDGE('',*,*,#1038,.F.);
#1072=ORIENTED_EDGE('',*,*,#227,.F.);
#1073=EDGE_LOOP('',(#1064,#1070,#1071,#1072));
#1074=FACE_BOUND('',#1073,.T.);
#1075=ADVANCED_FACE('F856',(#1074),#1056,.F.);
#1076=CARTESIAN_POINT('',(2.72,-2.,1.28));
#1077=DIRECTION('',(0.,1.,0.));
#1078=DIRECTION('',(0.,0.,1.));
#1079=AXIS2_PLACEMENT_3D('',#1076,#1077,#1078);
#1080=CYLINDRICAL_SURFACE('',#1079,0.4);
#1081=DIRECTION('',(0.,1.,0.));
#1082=VECTOR('',#1081,1.);
#1083=CARTESIAN_POINT('',(2.72,-2.,0.88));
#1084=LINE('',#1083,#1082);
#1085=CARTESIAN_POINT('',(2.72,2.,0.88));
#1086=VERTEX_POINT('',#1085);
#1087=EDGE_CURVE('E456',#209,#1086,#1084,.T.);
#1088=ORIENTED_EDGE('',*,*,#1087,.T.);
#1089=CARTESIAN_POINT('',(2.72,2.,1.28));
#1090=DIRECTION('',(0.,-1.,0.));
#1091=DIRECTION('',(0.,0.,1.));
#1092=AXIS2_PLACEMENT_3D('',#1089,#1090,#1091);
#1093=CIRCLE('',#1092,0.4);
#1094=EDGE_CURVE('E305',#1086,#1062,#1093,.T.);
#1095=ORIENTED_EDGE('',*,*,#1094,.T.);
#1096=ORIENTED_EDGE('',*,*,#1063,.F.);
#1097=ORIENTED_EDGE('',*,*,#219,.F.);
#1098=EDGE_LOOP('',(#1088,#1095,#1096,#1097));
#1099=FACE_BOUND('',#1098,.T.);
#1100=ADVANCED_FACE('F866',(#1099),#1080,.T.);
#1101=CARTESIAN_POINT('',(1.76715428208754,-2.,0.88));
#1102=DIRECTION('',(0.,0.,1.));
#1103=DIRECTION('',(1.,0.,0.));
#1104=AXIS2_PLACEMENT_3D('',#1101,#1102,#1103);
#1105=PLANE('',#1104);
#1106=DIRECTION('',(0.,1.,0.));
#1107=VECTOR('',#1106,1.);
#1108=CARTESIAN_POINT('',(0.8,-2.,0.88));
#1109=LINE('',#1108,#1107);
#1110=CARTESIAN_POINT('',(0.8,2.,0.88));
#1111=VERTEX_POINT('',#1110);
#1112=EDGE_CURVE('E458',#201,#1111,#1109,.T.);
#1113=ORIENTED_EDGE('',*,*,#1112,.T.);
#1114=DIRECTION('',(1.,0.,0.));
#1115=VECTOR('',#1114,1.);
#1116=CARTESIAN_POINT('',(1.76715428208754,2.,0.88));
#1117=LINE('',#1116,#1115);
#1118=EDGE_CURVE('E302',#1111,#1086,#1117,.T.);
#1119=ORIENTED_EDGE('',*,*,#1118,.T.);
#1120=ORIENTED_EDGE('',*,*,#1087,.F.);
#1121=ORIENTED_EDGE('',*,*,#210,.F.);
#1122=EDGE_LOOP('',(#1113,#1119,#1120,#1121));
#1123=FACE_BOUND('',#1122,.T.);
#1124=ADVANCED_FACE('F876',(#1123),#1105,.F.);
#1125=CARTESIAN_POINT('',(0.8,-2.,0.88));
#1126=DIRECTION('',(-1.,0.,0.));
#1127=DIRECTION('',(0.,0.,1.));
#1128=AXIS2_PLACEMENT_3D('',#1125,#1126,#1127);
#1129=PLANE('',#1128);
#1130=DIRECTION('',(0.,1.,0.));
#1131=VECTOR('',#1130,1.);
#1132=CARTESIAN_POINT('',(0.8,-2.,-0.879999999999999));
#1133=LINE('',#1132,#1131);
#1134=CARTESIAN_POINT('',(0.8,2.,-0.879999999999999));
#1135=VERTEX_POINT('',#1134);
#1136=EDGE_CURVE('E460',#193,#1135,#1133,.T.);
#1137=ORIENTED_EDGE('',*,*,#1136,.T.);
#1138=DIRECTION('',(0.,0.,1.));
#1139=VECTOR('',#1138,1.);
#1140=CARTESIAN_POINT('',(0.8,2.,0.88));
#1141=LINE('',#1140,#1139);
#1142=EDGE_CURVE('E299',#1135,#1111,#1141,.T.);
#1143=ORIENTED_EDGE('',*,*,#1142,.T.);
#1144=ORIENTED_EDGE('',*,*,#1112,.F.);
#1145=ORIENTED_EDGE('',*,*,#202,.F.);
#1146=EDGE_LOOP('',(#1137,#1143,#1144,#1145));
#1147=FACE_BOUND('',#1146,.T.);
#1148=ADVANCED_FACE('F887',(#1147),#1129,.F.);
#1149=CARTESIAN_POINT('',(0.8,-2.,-0.879999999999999));
#1150=DIRECTION('',(0.,0.,-1.));
#1151=DIRECTION('',(-1.,0.,0.));
#1152=AXIS2_PLACEMENT_3D('',#1149,#1150,#1151);
#1153=PLANE('',#1152);
#1154=DIRECTION('',(0.,1.,0.));
#1155=VECTOR('',#1154,1.);
#1156=CARTESIAN_POINT('',(2.72,-2.,-0.879999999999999));
#1157=LINE('',#1156,#1155);
#1158=CARTESIAN_POINT('',(2.72,2.,-0.879999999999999));
#1159=VERTEX_POINT('',#1158);
#1160=EDGE_CURVE('E462',#185,#1159,#1157,.T.);
#1161=ORIENTED_EDGE('',*,*,#1160,.T.);
#1162=DIRECTION('',(-1.,0.,0.));
#1163=VECTOR('',#1162,1.);
#1164=CARTESIAN_POINT('',(2.72,2.,-0.879999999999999));
#1165=LINE('',#1164,#1163);
#1166=EDGE_CURVE('E294',#1159,#1135,#1165,.T.);
#1167=ORIENTED_EDGE('',*,*,#1166,.T.);
#1168=ORIENTED_EDGE('',*,*,#1136,.F.);
#1169=ORIENTED_EDGE('',*,*,#194,.F.);
#1170=EDGE_LOOP('',(#1161,#1167,#1168,#1169));
#1171=FACE_BOUND('',#1170,.T.);
#1172=ADVANCED_FACE('F897',(#1171),#1153,.F.);
#1173=CARTESIAN_POINT('',(2.72,-2.,-1.28));
#1174=DIRECTION('',(0.,1.,0.));
#1175=DIRECTION('',(0.,0.,1.));
#1176=AXIS2_PLACEMENT_3D('',#1173,#1174,#1175);
#1177=CYLINDRICAL_SURFACE('',#1176,0.4);
#1178=DIRECTION('',(0.,1.,0.));
#1179=VECTOR('',#1178,1.);
#1180=CARTESIAN_POINT('',(3.12,-2.,-1.28));
#1181=LINE('',#1180,#1179);
#1182=CARTESIAN_POINT('',(3.12,2.,-1.28));
#1183=VERTEX_POINT('',#1182);
#1184=EDGE_CURVE('E278',#176,#1183,#1181,.T.);
#1185=ORIENTED_EDGE('',*,*,#1184,.T.);
#1186=CARTESIAN_POINT('',(2.72,2.,-1.28));
#1187=DIRECTION('',(0.,-1.,0.));
#1188=DIRECTION('',(0.,0.,-1.));
#1189=AXIS2_PLACEMENT_3D('',#1186,#1187,#1188);
#1190=CIRCLE('',#1189,0.4);
#1191=EDGE_CURVE('E292',#1183,#1159,#1190,.T.);
#1192=ORIENTED_EDGE('',*,*,#1191,.T.);
#1193=ORIENTED_EDGE('',*,*,#1160,.F.);
#1194=ORIENTED_EDGE('',*,*,#186,.F.);
#1195=EDGE_LOOP('',(#1185,#1192,#1193,#1194));
#1196=FACE_BOUND('',#1195,.T.);
#1197=ADVANCED_FACE('F908',(#1196),#1177,.T.);
#1198=CARTESIAN_POINT('',(3.12,-2.,-2.23284571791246));
#1199=DIRECTION('',(-1.,0.,0.));
#1200=DIRECTION('',(0.,0.,1.));
#1201=AXIS2_PLACEMENT_3D('',#1198,#1199,#1200);
#1202=PLANE('',#1201);
#1203=ORIENTED_EDGE('',*,*,#850,.T.);
#1204=DIRECTION('',(0.,0.,1.));
#1205=VECTOR('',#1204,1.);
#1206=CARTESIAN_POINT('',(3.12,2.,-2.23284571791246));
#1207=LINE('',#1206,#1205);
#1208=EDGE_CURVE('E271',#843,#1183,#1207,.T.);
#1209=ORIENTED_EDGE('',*,*,#1208,.T.);
#1210=ORIENTED_EDGE('',*,*,#1184,.F.);
#1211=ORIENTED_EDGE('',*,*,#177,.F.);
#1212=EDGE_LOOP('',(#1203,#1209,#1210,#1211));
#1213=FACE_BOUND('',#1212,.T.);
#1214=ADVANCED_FACE('F269',(#1213),#1202,.F.);
#1215=CARTESIAN_POINT('',(-4.,2.,0.));
#1216=DIRECTION('',(0.,1.,0.));
#1217=DIRECTION('',(0.,0.,1.));
#1218=AXIS2_PLACEMENT_3D('',#1215,#1216,#1217);
#1219=PLANE('',#1218);
#1220=ORIENTED_EDGE('',*,*,#41,.T.);
#1221=ORIENTED_EDGE('',*,*,#135,.T.);
#1222=ORIENTED_EDGE('',*,*,#105,.T.);
#1223=ORIENTED_EDGE('',*,*,#73,.T.);
#1224=EDGE_LOOP('',(#1220,#1221,#1222,#1223));
#1225=FACE_BOUND('',#1224,.T.);
#1226=ORIENTED_EDGE('',*,*,#817,.F.);
#1227=ORIENTED_EDGE('',*,*,#453,.F.);
#1228=ORIENTED_EDGE('',*,*,#482,.F.);
#1229=ORIENTED_EDGE('',*,*,#507,.F.);
#1230=ORIENTED_EDGE('',*,*,#531,.F.);
#1231=ORIENTED_EDGE('',*,*,#556,.F.);
#1232=ORIENTED_EDGE('',*,*,#580,.F.);
#1233=ORIENTED_EDGE('',*,*,#605,.F.);
#1234=ORIENTED_EDGE('',*,*,#629,.F.);
#1235=ORIENTED_EDGE('',*,*,#653,.F.);
#1236=ORIENTED_EDGE('',*,*,#677,.F.);
#1237=ORIENTED_EDGE('',*,*,#702,.F.);
#1238=ORIENTED_EDGE('',*,*,#726,.F.);
#1239=ORIENTED_EDGE('',*,*,#751,.F.);
#1240=ORIENTED_EDGE('',*,*,#775,.F.);
#1241=ORIENTED_EDGE('',*,*,#800,.F.);
#1242=EDGE_LOOP('',(#1226,#1227,#1228,#1229,#1230,#1231,#1232,#1233,#1234,#1235,#1236,#1237,
#1238,#1239,#1240,#1241));
#1243=FACE_BOUND('',#1242,.T.);
#1244=ORIENTED_EDGE('',*,*,#1208,.F.);
#1245=ORIENTED_EDGE('',*,*,#844,.F.);
#1246=ORIENTED_EDGE('',*,*,#873,.F.);
#1247=ORIENTED_EDGE('',*,*,#898,.F.);
#1248=ORIENTED_EDGE('',*,*,#922,.F.);
#1249=ORIENTED_EDGE('',*,*,#947,.F.);
#1250=ORIENTED_EDGE('',*,*,#971,.F.);
#1251=ORIENTED_EDGE('',*,*,#996,.F.);
#1252=ORIENTED_EDGE('',*,*,#1020,.F.);
#1253=ORIENTED_EDGE('',*,*,#1045,.F.);
#1254=ORIENTED_EDGE('',*,*,#1069,.F.);
#1255=ORIENTED_EDGE('',*,*,#1094,.F.);
#1256=ORIENTED_EDGE('',*,*,#1118,.F.);
#1257=ORIENTED_EDGE('',*,*,#1142,.F.);
#1258=ORIENTED_EDGE('',*,*,#1166,.F.);
#1259=ORIENTED_EDGE('',*,*,#1191,.F.);
#1260=EDGE_LOOP('',(#1244,#1245,#1246,#1247,#1248,#1249,#1250,#1251,#1252,#1253,#1254,#1255,
#1256,#1257,#1258,#1259));
#1261=FACE_BOUND('',#1260,.T.);
#1262=ADVANCED_FACE('F289',(#1225,#1243,#1261),#1219,.T.);
#1263=CLOSED_SHELL('',(#60,#91,#124,#146,#432,#464,#488,#513,#537,#562,#586,#611,#635,#659,#683,
#708,#732,#757,#781,#806,#823,#855,#879,#904,#928,#953,#977,#1002,#1026,#1051,#1075,#1100,#1124,
#1148,#1172,#1197,#1214,#1262));
#1264=MANIFOLD_SOLID_BREP('B2',#1263);
#1265=ADVANCED_BREP_SHAPE_REPRESENTATION('',(#18,#1264),#14);
#1266=SHAPE_DEFINITION_REPRESENTATION(#9,#1265);
ENDSEC;
END-ISO-10303-21;
